VERSION 5.7 ;
  NOWIREEXTENSIONATPIN ON ;
  DIVIDERCHAR "/" ;
  BUSBITCHARS "[]" ;
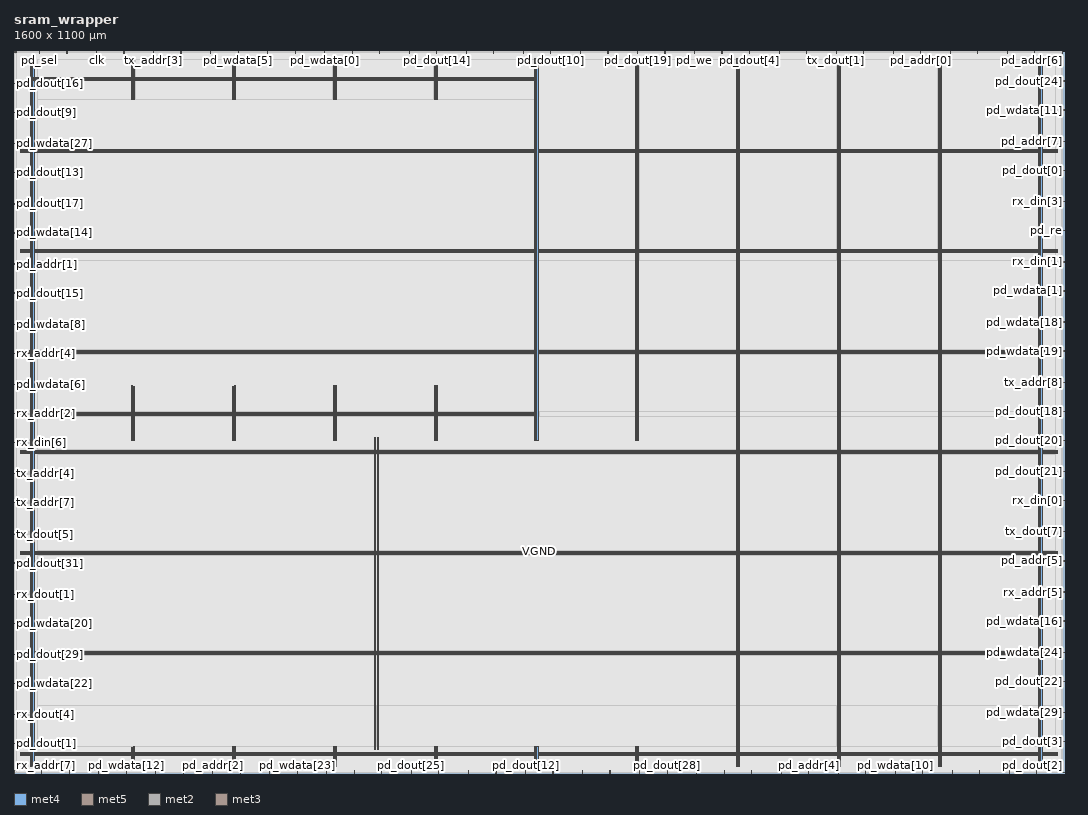
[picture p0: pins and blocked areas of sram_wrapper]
MACRO sram_wrapper
  CLASS BLOCK ;
  FOREIGN sram_wrapper ;
  ORIGIN 0.000 0.000 ;
  SIZE 1600.000 BY 1100.000 ;
  PIN VGND
    DIRECTION INOUT ;
    USE GROUND ;
    PORT
      LAYER met4 ;
        RECT 28.940 10.640 30.540 1088.240 ;
    END
    PORT
      LAYER met4 ;
        RECT 182.540 10.640 184.140 40.020 ;
    END
    PORT
      LAYER met4 ;
        RECT 182.540 506.440 184.140 589.400 ;
    END
    PORT
      LAYER met4 ;
        RECT 182.540 1026.520 184.140 1088.240 ;
    END
    PORT
      LAYER met4 ;
        RECT 336.140 10.640 337.740 40.020 ;
    END
    PORT
      LAYER met4 ;
        RECT 336.140 506.440 337.740 590.020 ;
    END
    PORT
      LAYER met4 ;
        RECT 336.140 1026.520 337.740 1088.240 ;
    END
    PORT
      LAYER met4 ;
        RECT 489.740 10.640 491.340 40.020 ;
    END
    PORT
      LAYER met4 ;
        RECT 489.740 506.440 491.340 590.020 ;
    END
    PORT
      LAYER met4 ;
        RECT 489.740 1026.520 491.340 1088.240 ;
    END
    PORT
      LAYER met4 ;
        RECT 643.340 10.640 644.940 40.020 ;
    END
    PORT
      LAYER met4 ;
        RECT 643.340 506.440 644.940 590.020 ;
    END
    PORT
      LAYER met4 ;
        RECT 643.340 1026.520 644.940 1088.240 ;
    END
    PORT
      LAYER met4 ;
        RECT 796.940 10.640 798.540 40.020 ;
    END
    PORT
      LAYER met4 ;
        RECT 796.940 506.440 798.540 1088.240 ;
    END
    PORT
      LAYER met4 ;
        RECT 950.540 10.640 952.140 40.020 ;
    END
    PORT
      LAYER met4 ;
        RECT 950.540 506.440 952.140 1088.240 ;
    END
    PORT
      LAYER met4 ;
        RECT 1104.140 10.640 1105.740 1088.240 ;
    END
    PORT
      LAYER met4 ;
        RECT 1257.740 10.640 1259.340 1088.240 ;
    END
    PORT
      LAYER met4 ;
        RECT 1411.340 10.640 1412.940 1088.240 ;
    END
    PORT
      LAYER met4 ;
        RECT 1564.940 10.640 1566.540 1088.240 ;
    END
    PORT
      LAYER met5 ;
        RECT 9.880 30.030 1590.000 31.630 ;
    END
    PORT
      LAYER met5 ;
        RECT 9.880 183.210 1590.000 184.810 ;
    END
    PORT
      LAYER met5 ;
        RECT 9.880 336.390 1590.000 337.990 ;
    END
    PORT
      LAYER met5 ;
        RECT 9.880 489.570 1590.000 491.170 ;
    END
    PORT
      LAYER met5 ;
        RECT 9.880 642.750 1590.000 644.350 ;
    END
    PORT
      LAYER met5 ;
        RECT 9.880 795.930 1590.000 797.530 ;
    END
    PORT
      LAYER met5 ;
        RECT 9.880 949.110 1590.000 950.710 ;
    END
    PORT
      LAYER met4 ;
        RECT 553.500 35.120 555.100 511.600 ;
    END
    PORT
      LAYER met5 ;
        RECT 25.640 548.300 798.540 549.900 ;
    END
    PORT
      LAYER met5 ;
        RECT 25.640 1058.300 798.540 1059.900 ;
    END
  END VGND
  PIN VPWR
    DIRECTION INOUT ;
    USE POWER ;
    PORT
      LAYER met4 ;
        RECT 25.640 10.640 27.240 1088.240 ;
    END
    PORT
      LAYER met4 ;
        RECT 179.240 10.640 180.840 39.400 ;
    END
    PORT
      LAYER met4 ;
        RECT 179.240 506.440 180.840 590.020 ;
    END
    PORT
      LAYER met4 ;
        RECT 179.240 1026.520 180.840 1088.240 ;
    END
    PORT
      LAYER met4 ;
        RECT 332.840 10.640 334.440 40.020 ;
    END
    PORT
      LAYER met4 ;
        RECT 332.840 506.440 334.440 589.400 ;
    END
    PORT
      LAYER met4 ;
        RECT 332.840 1026.520 334.440 1088.240 ;
    END
    PORT
      LAYER met4 ;
        RECT 486.440 10.640 488.040 40.020 ;
    END
    PORT
      LAYER met4 ;
        RECT 486.440 506.440 488.040 590.020 ;
    END
    PORT
      LAYER met4 ;
        RECT 486.440 1026.520 488.040 1088.240 ;
    END
    PORT
      LAYER met4 ;
        RECT 640.040 10.640 641.640 40.020 ;
    END
    PORT
      LAYER met4 ;
        RECT 640.040 506.440 641.640 590.020 ;
    END
    PORT
      LAYER met4 ;
        RECT 640.040 1026.520 641.640 1088.240 ;
    END
    PORT
      LAYER met4 ;
        RECT 793.640 10.640 795.240 40.020 ;
    END
    PORT
      LAYER met4 ;
        RECT 793.640 506.440 795.240 1088.240 ;
    END
    PORT
      LAYER met4 ;
        RECT 947.240 10.640 948.840 40.020 ;
    END
    PORT
      LAYER met4 ;
        RECT 947.240 506.440 948.840 1088.240 ;
    END
    PORT
      LAYER met4 ;
        RECT 1100.840 10.640 1102.440 1088.240 ;
    END
    PORT
      LAYER met4 ;
        RECT 1254.440 10.640 1256.040 1088.240 ;
    END
    PORT
      LAYER met4 ;
        RECT 1408.040 10.640 1409.640 1088.240 ;
    END
    PORT
      LAYER met4 ;
        RECT 1561.640 10.640 1563.240 1088.240 ;
    END
    PORT
      LAYER met5 ;
        RECT 9.880 26.730 1590.000 28.330 ;
    END
    PORT
      LAYER met5 ;
        RECT 9.880 179.910 1590.000 181.510 ;
    END
    PORT
      LAYER met5 ;
        RECT 9.880 333.090 1590.000 334.690 ;
    END
    PORT
      LAYER met5 ;
        RECT 9.880 486.270 1590.000 487.870 ;
    END
    PORT
      LAYER met5 ;
        RECT 9.880 639.450 1590.000 641.050 ;
    END
    PORT
      LAYER met5 ;
        RECT 9.880 792.630 1590.000 794.230 ;
    END
    PORT
      LAYER met5 ;
        RECT 9.880 945.810 1590.000 947.410 ;
    END
    PORT
      LAYER met4 ;
        RECT 549.820 35.120 551.420 511.600 ;
    END
    PORT
      LAYER met5 ;
        RECT 25.640 544.900 798.540 546.500 ;
    END
    PORT
      LAYER met5 ;
        RECT 25.640 1054.900 798.540 1056.500 ;
    END
  END VPWR
  PIN clk
    DIRECTION INPUT ;
    USE SIGNAL ;
    ANTENNAGATEAREA 1.286700 ;
    ANTENNADIFFAREA 0.434700 ;
    PORT
      LAYER met2 ;
        RECT 125.670 1096.000 125.950 1100.000 ;
    END
  END clk
  PIN pd_addr[0]
    DIRECTION INPUT ;
    USE SIGNAL ;
    ANTENNAGATEAREA 0.990000 ;
    PORT
      LAYER met2 ;
        RECT 1381.470 1096.000 1381.750 1100.000 ;
    END
  END pd_addr[0]
  PIN pd_addr[1]
    DIRECTION INPUT ;
    USE SIGNAL ;
    ANTENNAGATEAREA 0.495000 ;
    PORT
      LAYER met3 ;
        RECT 0.000 775.240 4.000 775.840 ;
    END
  END pd_addr[1]
  PIN pd_addr[2]
    DIRECTION INPUT ;
    USE SIGNAL ;
    ANTENNAGATEAREA 0.742500 ;
    PORT
      LAYER met2 ;
        RECT 302.770 0.000 303.050 4.000 ;
    END
  END pd_addr[2]
  PIN pd_addr[3]
    DIRECTION INPUT ;
    USE SIGNAL ;
    ANTENNAGATEAREA 0.990000 ;
    PORT
      LAYER met2 ;
        RECT 1468.410 1096.000 1468.690 1100.000 ;
    END
  END pd_addr[3]
  PIN pd_addr[4]
    DIRECTION INPUT ;
    USE SIGNAL ;
    ANTENNAGATEAREA 0.990000 ;
    PORT
      LAYER met2 ;
        RECT 1210.810 0.000 1211.090 4.000 ;
    END
  END pd_addr[4]
  PIN pd_addr[5]
    DIRECTION INPUT ;
    USE SIGNAL ;
    ANTENNAGATEAREA 0.990000 ;
    PORT
      LAYER met3 ;
        RECT 1596.000 323.040 1600.000 323.640 ;
    END
  END pd_addr[5]
  PIN pd_addr[6]
    DIRECTION INPUT ;
    USE SIGNAL ;
    ANTENNAGATEAREA 0.990000 ;
    PORT
      LAYER met2 ;
        RECT 1597.210 1096.000 1597.490 1100.000 ;
    END
  END pd_addr[6]
  PIN pd_addr[7]
    DIRECTION INPUT ;
    USE SIGNAL ;
    ANTENNAGATEAREA 0.990000 ;
    PORT
      LAYER met3 ;
        RECT 1596.000 962.240 1600.000 962.840 ;
    END
  END pd_addr[7]
  PIN pd_addr[8]
    DIRECTION INPUT ;
    USE SIGNAL ;
    ANTENNAGATEAREA 0.742500 ;
    PORT
      LAYER met2 ;
        RECT 904.910 1096.000 905.190 1100.000 ;
    END
  END pd_addr[8]
  PIN pd_dout[0]
    DIRECTION OUTPUT TRISTATE ;
    USE SIGNAL ;
    ANTENNADIFFAREA 0.445500 ;
    PORT
      LAYER met3 ;
        RECT 1596.000 918.040 1600.000 918.640 ;
    END
  END pd_dout[0]
  PIN pd_dout[10]
    DIRECTION OUTPUT TRISTATE ;
    USE SIGNAL ;
    ANTENNADIFFAREA 0.795200 ;
    PORT
      LAYER met2 ;
        RECT 817.970 1096.000 818.250 1100.000 ;
    END
  END pd_dout[10]
  PIN pd_dout[11]
    DIRECTION OUTPUT TRISTATE ;
    USE SIGNAL ;
    ANTENNADIFFAREA 0.795200 ;
    PORT
      LAYER met2 ;
        RECT 1555.350 1096.000 1555.630 1100.000 ;
    END
  END pd_dout[11]
  PIN pd_dout[12]
    DIRECTION OUTPUT TRISTATE ;
    USE SIGNAL ;
    ANTENNADIFFAREA 0.445500 ;
    PORT
      LAYER met2 ;
        RECT 779.330 0.000 779.610 4.000 ;
    END
  END pd_dout[12]
  PIN pd_dout[13]
    DIRECTION OUTPUT TRISTATE ;
    USE SIGNAL ;
    ANTENNADIFFAREA 0.445500 ;
    PORT
      LAYER met3 ;
        RECT 0.000 914.640 4.000 915.240 ;
    END
  END pd_dout[13]
  PIN pd_dout[14]
    DIRECTION OUTPUT TRISTATE ;
    USE SIGNAL ;
    ANTENNADIFFAREA 0.795200 ;
    PORT
      LAYER met2 ;
        RECT 644.090 1096.000 644.370 1100.000 ;
    END
  END pd_dout[14]
  PIN pd_dout[15]
    DIRECTION OUTPUT TRISTATE ;
    USE SIGNAL ;
    ANTENNADIFFAREA 0.445500 ;
    PORT
      LAYER met3 ;
        RECT 0.000 731.040 4.000 731.640 ;
    END
  END pd_dout[15]
  PIN pd_dout[16]
    DIRECTION OUTPUT TRISTATE ;
    USE SIGNAL ;
    ANTENNADIFFAREA 0.445500 ;
    PORT
      LAYER met3 ;
        RECT 0.000 1050.640 4.000 1051.240 ;
    END
  END pd_dout[16]
  PIN pd_dout[17]
    DIRECTION OUTPUT TRISTATE ;
    USE SIGNAL ;
    ANTENNADIFFAREA 0.445500 ;
    PORT
      LAYER met3 ;
        RECT 0.000 867.040 4.000 867.640 ;
    END
  END pd_dout[17]
  PIN pd_dout[18]
    DIRECTION OUTPUT TRISTATE ;
    USE SIGNAL ;
    ANTENNADIFFAREA 0.445500 ;
    PORT
      LAYER met3 ;
        RECT 1596.000 550.840 1600.000 551.440 ;
    END
  END pd_dout[18]
  PIN pd_dout[19]
    DIRECTION OUTPUT TRISTATE ;
    USE SIGNAL ;
    ANTENNADIFFAREA 0.795200 ;
    PORT
      LAYER met2 ;
        RECT 949.990 1096.000 950.270 1100.000 ;
    END
  END pd_dout[19]
  PIN pd_dout[1]
    DIRECTION OUTPUT TRISTATE ;
    USE SIGNAL ;
    ANTENNADIFFAREA 0.445500 ;
    PORT
      LAYER met3 ;
        RECT 0.000 44.240 4.000 44.840 ;
    END
  END pd_dout[1]
  PIN pd_dout[20]
    DIRECTION OUTPUT TRISTATE ;
    USE SIGNAL ;
    ANTENNADIFFAREA 0.445500 ;
    PORT
      LAYER met3 ;
        RECT 1596.000 506.640 1600.000 507.240 ;
    END
  END pd_dout[20]
  PIN pd_dout[21]
    DIRECTION OUTPUT TRISTATE ;
    USE SIGNAL ;
    ANTENNADIFFAREA 0.445500 ;
    PORT
      LAYER met3 ;
        RECT 1596.000 459.040 1600.000 459.640 ;
    END
  END pd_dout[21]
  PIN pd_dout[22]
    DIRECTION OUTPUT TRISTATE ;
    USE SIGNAL ;
    ANTENNADIFFAREA 0.445500 ;
    PORT
      LAYER met3 ;
        RECT 1596.000 139.440 1600.000 140.040 ;
    END
  END pd_dout[22]
  PIN pd_dout[23]
    DIRECTION OUTPUT TRISTATE ;
    USE SIGNAL ;
    ANTENNADIFFAREA 0.795200 ;
    PORT
      LAYER met2 ;
        RECT 991.850 1096.000 992.130 1100.000 ;
    END
  END pd_dout[23]
  PIN pd_dout[24]
    DIRECTION OUTPUT TRISTATE ;
    USE SIGNAL ;
    ANTENNADIFFAREA 0.445500 ;
    PORT
      LAYER met3 ;
        RECT 1596.000 1054.040 1600.000 1054.640 ;
    END
  END pd_dout[24]
  PIN pd_dout[25]
    DIRECTION OUTPUT TRISTATE ;
    USE SIGNAL ;
    ANTENNADIFFAREA 0.445500 ;
    PORT
      LAYER met2 ;
        RECT 605.450 0.000 605.730 4.000 ;
    END
  END pd_dout[25]
  PIN pd_dout[26]
    DIRECTION OUTPUT TRISTATE ;
    USE SIGNAL ;
    ANTENNADIFFAREA 0.445500 ;
    PORT
      LAYER met2 ;
        RECT 518.510 0.000 518.790 4.000 ;
    END
  END pd_dout[26]
  PIN pd_dout[27]
    DIRECTION OUTPUT TRISTATE ;
    USE SIGNAL ;
    ANTENNADIFFAREA 0.445500 ;
    PORT
      LAYER met2 ;
        RECT 389.710 0.000 389.990 4.000 ;
    END
  END pd_dout[27]
  PIN pd_dout[28]
    DIRECTION OUTPUT TRISTATE ;
    USE SIGNAL ;
    ANTENNADIFFAREA 0.445500 ;
    PORT
      LAYER met2 ;
        RECT 995.070 0.000 995.350 4.000 ;
    END
  END pd_dout[28]
  PIN pd_dout[29]
    DIRECTION OUTPUT TRISTATE ;
    USE SIGNAL ;
    ANTENNADIFFAREA 0.445500 ;
    PORT
      LAYER met3 ;
        RECT 0.000 180.240 4.000 180.840 ;
    END
  END pd_dout[29]
  PIN pd_dout[2]
    DIRECTION OUTPUT TRISTATE ;
    USE SIGNAL ;
    ANTENNADIFFAREA 0.445500 ;
    PORT
      LAYER met2 ;
        RECT 1558.570 0.000 1558.850 4.000 ;
    END
  END pd_dout[2]
  PIN pd_dout[30]
    DIRECTION OUTPUT TRISTATE ;
    USE SIGNAL ;
    ANTENNADIFFAREA 0.445500 ;
    PORT
      LAYER met2 ;
        RECT 344.630 0.000 344.910 4.000 ;
    END
  END pd_dout[30]
  PIN pd_dout[31]
    DIRECTION OUTPUT TRISTATE ;
    USE SIGNAL ;
    ANTENNADIFFAREA 0.445500 ;
    PORT
      LAYER met3 ;
        RECT 0.000 319.640 4.000 320.240 ;
    END
  END pd_dout[31]
  PIN pd_dout[3]
    DIRECTION OUTPUT TRISTATE ;
    USE SIGNAL ;
    ANTENNADIFFAREA 0.445500 ;
    PORT
      LAYER met3 ;
        RECT 1596.000 47.640 1600.000 48.240 ;
    END
  END pd_dout[3]
  PIN pd_dout[4]
    DIRECTION OUTPUT TRISTATE ;
    USE SIGNAL ;
    ANTENNADIFFAREA 0.795200 ;
    PORT
      LAYER met2 ;
        RECT 1120.650 1096.000 1120.930 1100.000 ;
    END
  END pd_dout[4]
  PIN pd_dout[5]
    DIRECTION OUTPUT TRISTATE ;
    USE SIGNAL ;
    ANTENNADIFFAREA 0.795200 ;
    PORT
      LAYER met2 ;
        RECT 602.230 1096.000 602.510 1100.000 ;
    END
  END pd_dout[5]
  PIN pd_dout[6]
    DIRECTION OUTPUT TRISTATE ;
    USE SIGNAL ;
    ANTENNADIFFAREA 0.795200 ;
    PORT
      LAYER met2 ;
        RECT 776.110 1096.000 776.390 1100.000 ;
    END
  END pd_dout[6]
  PIN pd_dout[7]
    DIRECTION OUTPUT TRISTATE ;
    USE SIGNAL ;
    ANTENNADIFFAREA 0.795200 ;
    PORT
      LAYER met2 ;
        RECT 1207.590 1096.000 1207.870 1100.000 ;
    END
  END pd_dout[7]
  PIN pd_dout[8]
    DIRECTION OUTPUT TRISTATE ;
    USE SIGNAL ;
    ANTENNADIFFAREA 0.445500 ;
    PORT
      LAYER met2 ;
        RECT 1082.010 0.000 1082.290 4.000 ;
    END
  END pd_dout[8]
  PIN pd_dout[9]
    DIRECTION OUTPUT TRISTATE ;
    USE SIGNAL ;
    ANTENNADIFFAREA 0.445500 ;
    PORT
      LAYER met3 ;
        RECT 0.000 1006.440 4.000 1007.040 ;
    END
  END pd_dout[9]
  PIN pd_re
    DIRECTION INPUT ;
    USE SIGNAL ;
    ANTENNAGATEAREA 0.742500 ;
    PORT
      LAYER met3 ;
        RECT 1596.000 826.240 1600.000 826.840 ;
    END
  END pd_re
  PIN pd_sel
    DIRECTION INPUT ;
    USE SIGNAL ;
    ANTENNAGATEAREA 0.742500 ;
    PORT
      LAYER met2 ;
        RECT 38.730 1096.000 39.010 1100.000 ;
    END
  END pd_sel
  PIN pd_wdata[0]
    DIRECTION INPUT ;
    USE SIGNAL ;
    ANTENNAGATEAREA 0.247500 ;
    PORT
      LAYER met2 ;
        RECT 473.430 1096.000 473.710 1100.000 ;
    END
  END pd_wdata[0]
  PIN pd_wdata[10]
    DIRECTION INPUT ;
    USE SIGNAL ;
    ANTENNAGATEAREA 0.852000 ;
    PORT
      LAYER met2 ;
        RECT 1342.830 0.000 1343.110 4.000 ;
    END
  END pd_wdata[10]
  PIN pd_wdata[11]
    DIRECTION INPUT ;
    USE SIGNAL ;
    ANTENNAGATEAREA 0.990000 ;
    PORT
      LAYER met3 ;
        RECT 1596.000 1009.840 1600.000 1010.440 ;
    END
  END pd_wdata[11]
  PIN pd_wdata[12]
    DIRECTION INPUT ;
    USE SIGNAL ;
    ANTENNAGATEAREA 0.247500 ;
    PORT
      LAYER met2 ;
        RECT 170.750 0.000 171.030 4.000 ;
    END
  END pd_wdata[12]
  PIN pd_wdata[13]
    DIRECTION INPUT ;
    USE SIGNAL ;
    ANTENNAGATEAREA 0.247500 ;
    PORT
      LAYER met3 ;
        RECT 0.000 1098.240 4.000 1098.840 ;
    END
  END pd_wdata[13]
  PIN pd_wdata[14]
    DIRECTION INPUT ;
    USE SIGNAL ;
    ANTENNAGATEAREA 0.213000 ;
    PORT
      LAYER met3 ;
        RECT 0.000 822.840 4.000 823.440 ;
    END
  END pd_wdata[14]
  PIN pd_wdata[15]
    DIRECTION INPUT ;
    USE SIGNAL ;
    ANTENNAGATEAREA 0.742500 ;
    PORT
      LAYER met2 ;
        RECT 821.190 0.000 821.470 4.000 ;
    END
  END pd_wdata[15]
  PIN pd_wdata[16]
    DIRECTION INPUT ;
    USE SIGNAL ;
    ANTENNAGATEAREA 0.852000 ;
    PORT
      LAYER met3 ;
        RECT 1596.000 231.240 1600.000 231.840 ;
    END
  END pd_wdata[16]
  PIN pd_wdata[17]
    DIRECTION INPUT ;
    USE SIGNAL ;
    ANTENNAGATEAREA 0.990000 ;
    PORT
      LAYER met2 ;
        RECT 1255.890 0.000 1256.170 4.000 ;
    END
  END pd_wdata[17]
  PIN pd_wdata[18]
    DIRECTION INPUT ;
    USE SIGNAL ;
    ANTENNAGATEAREA 0.742500 ;
    PORT
      LAYER met3 ;
        RECT 1596.000 686.840 1600.000 687.440 ;
    END
  END pd_wdata[18]
  PIN pd_wdata[19]
    DIRECTION INPUT ;
    USE SIGNAL ;
    ANTENNAGATEAREA 0.742500 ;
    PORT
      LAYER met3 ;
        RECT 1596.000 642.640 1600.000 643.240 ;
    END
  END pd_wdata[19]
  PIN pd_wdata[1]
    DIRECTION INPUT ;
    USE SIGNAL ;
    ANTENNAGATEAREA 0.990000 ;
    PORT
      LAYER met3 ;
        RECT 1596.000 734.440 1600.000 735.040 ;
    END
  END pd_wdata[1]
  PIN pd_wdata[20]
    DIRECTION INPUT ;
    USE SIGNAL ;
    ANTENNAGATEAREA 0.247500 ;
    PORT
      LAYER met3 ;
        RECT 0.000 227.840 4.000 228.440 ;
    END
  END pd_wdata[20]
  PIN pd_wdata[21]
    DIRECTION INPUT ;
    USE SIGNAL ;
    ANTENNAGATEAREA 0.495000 ;
    PORT
      LAYER met2 ;
        RECT 863.050 1096.000 863.330 1100.000 ;
    END
  END pd_wdata[21]
  PIN pd_wdata[22]
    DIRECTION INPUT ;
    USE SIGNAL ;
    ANTENNAGATEAREA 0.247500 ;
    PORT
      LAYER met3 ;
        RECT 0.000 136.040 4.000 136.640 ;
    END
  END pd_wdata[22]
  PIN pd_wdata[23]
    DIRECTION INPUT ;
    USE SIGNAL ;
    ANTENNAGATEAREA 0.247500 ;
    PORT
      LAYER met2 ;
        RECT 431.570 0.000 431.850 4.000 ;
    END
  END pd_wdata[23]
  PIN pd_wdata[24]
    DIRECTION INPUT ;
    USE SIGNAL ;
    ANTENNAGATEAREA 0.852000 ;
    PORT
      LAYER met3 ;
        RECT 1596.000 183.640 1600.000 184.240 ;
    END
  END pd_wdata[24]
  PIN pd_wdata[25]
    DIRECTION INPUT ;
    USE SIGNAL ;
    ANTENNAGATEAREA 0.247500 ;
    PORT
      LAYER met2 ;
        RECT 557.150 1096.000 557.430 1100.000 ;
    END
  END pd_wdata[25]
  PIN pd_wdata[26]
    DIRECTION INPUT ;
    USE SIGNAL ;
    ANTENNAGATEAREA 0.247500 ;
    PORT
      LAYER met2 ;
        RECT 428.350 1096.000 428.630 1100.000 ;
    END
  END pd_wdata[26]
  PIN pd_wdata[27]
    DIRECTION INPUT ;
    USE SIGNAL ;
    ANTENNAGATEAREA 0.247500 ;
    PORT
      LAYER met3 ;
        RECT 0.000 958.840 4.000 959.440 ;
    END
  END pd_wdata[27]
  PIN pd_wdata[28]
    DIRECTION INPUT ;
    USE SIGNAL ;
    ANTENNAGATEAREA 0.990000 ;
    PORT
      LAYER met2 ;
        RECT 1297.750 0.000 1298.030 4.000 ;
    END
  END pd_wdata[28]
  PIN pd_wdata[29]
    DIRECTION INPUT ;
    USE SIGNAL ;
    ANTENNAGATEAREA 0.990000 ;
    PORT
      LAYER met3 ;
        RECT 1596.000 91.840 1600.000 92.440 ;
    END
  END pd_wdata[29]
  PIN pd_wdata[2]
    DIRECTION INPUT ;
    USE SIGNAL ;
    ANTENNAGATEAREA 0.990000 ;
    PORT
      LAYER met2 ;
        RECT 1426.550 1096.000 1426.830 1100.000 ;
    END
  END pd_wdata[2]
  PIN pd_wdata[30]
    DIRECTION INPUT ;
    USE SIGNAL ;
    ANTENNAGATEAREA 0.990000 ;
    PORT
      LAYER met2 ;
        RECT 1471.630 0.000 1471.910 4.000 ;
    END
  END pd_wdata[30]
  PIN pd_wdata[31]
    DIRECTION INPUT ;
    USE SIGNAL ;
    ANTENNAGATEAREA 0.742500 ;
    PORT
      LAYER met2 ;
        RECT 1123.870 0.000 1124.150 4.000 ;
    END
  END pd_wdata[31]
  PIN pd_wdata[3]
    DIRECTION INPUT ;
    USE SIGNAL ;
    ANTENNAGATEAREA 0.426000 ;
    PORT
      LAYER met2 ;
        RECT 560.370 0.000 560.650 4.000 ;
    END
  END pd_wdata[3]
  PIN pd_wdata[4]
    DIRECTION INPUT ;
    USE SIGNAL ;
    ANTENNAGATEAREA 0.426000 ;
    PORT
      LAYER met2 ;
        RECT 689.170 1096.000 689.450 1100.000 ;
    END
  END pd_wdata[4]
  PIN pd_wdata[5]
    DIRECTION INPUT ;
    USE SIGNAL ;
    ANTENNAGATEAREA 0.247500 ;
    PORT
      LAYER met2 ;
        RECT 341.410 1096.000 341.690 1100.000 ;
    END
  END pd_wdata[5]
  PIN pd_wdata[6]
    DIRECTION INPUT ;
    USE SIGNAL ;
    ANTENNAGATEAREA 0.126000 ;
    PORT
      LAYER met3 ;
        RECT 0.000 591.640 4.000 592.240 ;
    END
  END pd_wdata[6]
  PIN pd_wdata[7]
    DIRECTION INPUT ;
    USE SIGNAL ;
    ANTENNAGATEAREA 0.990000 ;
    PORT
      LAYER met2 ;
        RECT 1429.770 0.000 1430.050 4.000 ;
    END
  END pd_wdata[7]
  PIN pd_wdata[8]
    DIRECTION INPUT ;
    USE SIGNAL ;
    ANTENNAGATEAREA 0.213000 ;
    PORT
      LAYER met3 ;
        RECT 0.000 683.440 4.000 684.040 ;
    END
  END pd_wdata[8]
  PIN pd_wdata[9]
    DIRECTION INPUT ;
    USE SIGNAL ;
    ANTENNAGATEAREA 0.247500 ;
    PORT
      LAYER met2 ;
        RECT 386.490 1096.000 386.770 1100.000 ;
    END
  END pd_wdata[9]
  PIN pd_we
    DIRECTION INPUT ;
    USE SIGNAL ;
    ANTENNAGATEAREA 0.495000 ;
    PORT
      LAYER met2 ;
        RECT 1036.930 1096.000 1037.210 1100.000 ;
    END
  END pd_we
  PIN rx_addr[0]
    DIRECTION INPUT ;
    USE SIGNAL ;
    ANTENNAGATEAREA 0.742500 ;
    PORT
      LAYER met2 ;
        RECT 953.210 0.000 953.490 4.000 ;
    END
  END rx_addr[0]
  PIN rx_addr[1]
    DIRECTION INPUT ;
    USE SIGNAL ;
    ANTENNAGATEAREA 0.247500 ;
    PORT
      LAYER met2 ;
        RECT 128.890 0.000 129.170 4.000 ;
    END
  END rx_addr[1]
  PIN rx_addr[2]
    DIRECTION INPUT ;
    USE SIGNAL ;
    ANTENNAGATEAREA 0.426000 ;
    PORT
      LAYER met3 ;
        RECT 0.000 547.440 4.000 548.040 ;
    END
  END rx_addr[2]
  PIN rx_addr[3]
    DIRECTION INPUT ;
    USE SIGNAL ;
    ANTENNAGATEAREA 0.852000 ;
    PORT
      LAYER met2 ;
        RECT 1384.690 0.000 1384.970 4.000 ;
    END
  END rx_addr[3]
  PIN rx_addr[4]
    DIRECTION INPUT ;
    USE SIGNAL ;
    ANTENNAGATEAREA 0.495000 ;
    PORT
      LAYER met3 ;
        RECT 0.000 639.240 4.000 639.840 ;
    END
  END rx_addr[4]
  PIN rx_addr[5]
    DIRECTION INPUT ;
    USE SIGNAL ;
    ANTENNAGATEAREA 0.852000 ;
    PORT
      LAYER met3 ;
        RECT 1596.000 275.440 1600.000 276.040 ;
    END
  END rx_addr[5]
  PIN rx_addr[6]
    DIRECTION INPUT ;
    USE SIGNAL ;
    ANTENNAGATEAREA 0.742500 ;
    PORT
      LAYER met2 ;
        RECT 1040.150 0.000 1040.430 4.000 ;
    END
  END rx_addr[6]
  PIN rx_addr[7]
    DIRECTION INPUT ;
    USE SIGNAL ;
    ANTENNAGATEAREA 0.247500 ;
    PORT
      LAYER met2 ;
        RECT 41.950 0.000 42.230 4.000 ;
    END
  END rx_addr[7]
  PIN rx_addr[8]
    DIRECTION INPUT ;
    USE SIGNAL ;
    ANTENNAGATEAREA 0.990000 ;
    PORT
      LAYER met3 ;
        RECT 1596.000 0.040 1600.000 0.640 ;
    END
  END rx_addr[8]
  PIN rx_addr[9]
    DIRECTION INPUT ;
    USE SIGNAL ;
    ANTENNAGATEAREA 0.742500 ;
    PORT
      LAYER met2 ;
        RECT 167.530 1096.000 167.810 1100.000 ;
    END
  END rx_addr[9]
  PIN rx_din[0]
    DIRECTION INPUT ;
    USE SIGNAL ;
    ANTENNAGATEAREA 0.990000 ;
    PORT
      LAYER met3 ;
        RECT 1596.000 414.840 1600.000 415.440 ;
    END
  END rx_din[0]
  PIN rx_din[1]
    DIRECTION INPUT ;
    USE SIGNAL ;
    ANTENNAGATEAREA 0.990000 ;
    PORT
      LAYER met3 ;
        RECT 1596.000 778.640 1600.000 779.240 ;
    END
  END rx_din[1]
  PIN rx_din[2]
    DIRECTION INPUT ;
    USE SIGNAL ;
    ANTENNAGATEAREA 0.495000 ;
    PORT
      LAYER met2 ;
        RECT 1168.950 0.000 1169.230 4.000 ;
    END
  END rx_din[2]
  PIN rx_din[3]
    DIRECTION INPUT ;
    USE SIGNAL ;
    ANTENNAGATEAREA 0.990000 ;
    PORT
      LAYER met3 ;
        RECT 1596.000 870.440 1600.000 871.040 ;
    END
  END rx_din[3]
  PIN rx_din[4]
    DIRECTION INPUT ;
    USE SIGNAL ;
    ANTENNAGATEAREA 0.213000 ;
    PORT
      LAYER met2 ;
        RECT 692.390 0.000 692.670 4.000 ;
    END
  END rx_din[4]
  PIN rx_din[5]
    DIRECTION INPUT ;
    USE SIGNAL ;
    ANTENNAGATEAREA 0.495000 ;
    PORT
      LAYER met2 ;
        RECT 254.470 1096.000 254.750 1100.000 ;
    END
  END rx_din[5]
  PIN rx_din[6]
    DIRECTION INPUT ;
    USE SIGNAL ;
    ANTENNAGATEAREA 0.247500 ;
    PORT
      LAYER met3 ;
        RECT 0.000 503.240 4.000 503.840 ;
    END
  END rx_din[6]
  PIN rx_din[7]
    DIRECTION INPUT ;
    USE SIGNAL ;
    ANTENNAGATEAREA 0.126000 ;
    PORT
      LAYER met2 ;
        RECT 0.090 0.000 0.370 4.000 ;
    END
  END rx_din[7]
  PIN rx_dout[0]
    DIRECTION OUTPUT TRISTATE ;
    USE SIGNAL ;
    ANTENNADIFFAREA 0.445500 ;
    PORT
      LAYER met2 ;
        RECT 866.270 0.000 866.550 4.000 ;
    END
  END rx_dout[0]
  PIN rx_dout[1]
    DIRECTION OUTPUT TRISTATE ;
    USE SIGNAL ;
    ANTENNADIFFAREA 0.445500 ;
    PORT
      LAYER met3 ;
        RECT 0.000 272.040 4.000 272.640 ;
    END
  END rx_dout[1]
  PIN rx_dout[2]
    DIRECTION OUTPUT TRISTATE ;
    USE SIGNAL ;
    ANTENNADIFFAREA 0.795200 ;
    PORT
      LAYER met2 ;
        RECT 731.030 1096.000 731.310 1100.000 ;
    END
  END rx_dout[2]
  PIN rx_dout[3]
    DIRECTION OUTPUT TRISTATE ;
    USE SIGNAL ;
    ANTENNADIFFAREA 0.795200 ;
    PORT
      LAYER met2 ;
        RECT 1165.730 1096.000 1166.010 1100.000 ;
    END
  END rx_dout[3]
  PIN rx_dout[4]
    DIRECTION OUTPUT TRISTATE ;
    USE SIGNAL ;
    ANTENNADIFFAREA 0.445500 ;
    PORT
      LAYER met3 ;
        RECT 0.000 88.440 4.000 89.040 ;
    END
  END rx_dout[4]
  PIN rx_dout[5]
    DIRECTION OUTPUT TRISTATE ;
    USE SIGNAL ;
    ANTENNADIFFAREA 0.445500 ;
    PORT
      LAYER met2 ;
        RECT 215.830 0.000 216.110 4.000 ;
    END
  END rx_dout[5]
  PIN rx_dout[6]
    DIRECTION OUTPUT TRISTATE ;
    USE SIGNAL ;
    ANTENNADIFFAREA 0.445500 ;
    PORT
      LAYER met2 ;
        RECT 83.810 0.000 84.090 4.000 ;
    END
  END rx_dout[6]
  PIN rx_dout[7]
    DIRECTION OUTPUT TRISTATE ;
    USE SIGNAL ;
    ANTENNADIFFAREA 0.795200 ;
    PORT
      LAYER met2 ;
        RECT 1339.610 1096.000 1339.890 1100.000 ;
    END
  END rx_dout[7]
  PIN rx_we
    DIRECTION INPUT ;
    USE SIGNAL ;
    ANTENNAGATEAREA 0.742500 ;
    PORT
      LAYER met2 ;
        RECT 1078.790 1096.000 1079.070 1100.000 ;
    END
  END rx_we
  PIN tx_addr[0]
    DIRECTION INPUT ;
    USE SIGNAL ;
    ANTENNAGATEAREA 0.426000 ;
    PORT
      LAYER met2 ;
        RECT 647.310 0.000 647.590 4.000 ;
    END
  END tx_addr[0]
  PIN tx_addr[1]
    DIRECTION INPUT ;
    USE SIGNAL ;
    ANTENNAGATEAREA 0.990000 ;
    PORT
      LAYER met2 ;
        RECT 1513.490 1096.000 1513.770 1100.000 ;
    END
  END tx_addr[1]
  PIN tx_addr[2]
    DIRECTION INPUT ;
    USE SIGNAL ;
    ANTENNAGATEAREA 0.742500 ;
    PORT
      LAYER met2 ;
        RECT 1516.710 0.000 1516.990 4.000 ;
    END
  END tx_addr[2]
  PIN tx_addr[3]
    DIRECTION INPUT ;
    USE SIGNAL ;
    ANTENNAGATEAREA 0.990000 ;
    PORT
      LAYER met2 ;
        RECT 212.610 1096.000 212.890 1100.000 ;
    END
  END tx_addr[3]
  PIN tx_addr[4]
    DIRECTION INPUT ;
    USE SIGNAL ;
    ANTENNAGATEAREA 0.742500 ;
    PORT
      LAYER met3 ;
        RECT 0.000 455.640 4.000 456.240 ;
    END
  END tx_addr[4]
  PIN tx_addr[5]
    DIRECTION INPUT ;
    USE SIGNAL ;
    ANTENNAGATEAREA 0.495000 ;
    PORT
      LAYER met2 ;
        RECT 257.690 0.000 257.970 4.000 ;
    END
  END tx_addr[5]
  PIN tx_addr[6]
    DIRECTION INPUT ;
    USE SIGNAL ;
    ANTENNAGATEAREA 0.247500 ;
    PORT
      LAYER met2 ;
        RECT 476.650 0.000 476.930 4.000 ;
    END
  END tx_addr[6]
  PIN tx_addr[7]
    DIRECTION INPUT ;
    USE SIGNAL ;
    ANTENNAGATEAREA 0.742500 ;
    PORT
      LAYER met3 ;
        RECT 0.000 411.440 4.000 412.040 ;
    END
  END tx_addr[7]
  PIN tx_addr[8]
    DIRECTION INPUT ;
    USE SIGNAL ;
    ANTENNAGATEAREA 0.852000 ;
    PORT
      LAYER met3 ;
        RECT 1596.000 595.040 1600.000 595.640 ;
    END
  END tx_addr[8]
  PIN tx_addr[9]
    DIRECTION INPUT ;
    USE SIGNAL ;
    ANTENNAGATEAREA 0.247500 ;
    PORT
      LAYER met2 ;
        RECT 734.250 0.000 734.530 4.000 ;
    END
  END tx_addr[9]
  PIN tx_dout[0]
    DIRECTION OUTPUT TRISTATE ;
    USE SIGNAL ;
    ANTENNADIFFAREA 0.795200 ;
    PORT
      LAYER met2 ;
        RECT 1294.530 1096.000 1294.810 1100.000 ;
    END
  END tx_dout[0]
  PIN tx_dout[1]
    DIRECTION OUTPUT TRISTATE ;
    USE SIGNAL ;
    ANTENNADIFFAREA 0.795200 ;
    PORT
      LAYER met2 ;
        RECT 1252.670 1096.000 1252.950 1100.000 ;
    END
  END tx_dout[1]
  PIN tx_dout[2]
    DIRECTION OUTPUT TRISTATE ;
    USE SIGNAL ;
    ANTENNADIFFAREA 0.795200 ;
    PORT
      LAYER met2 ;
        RECT 299.550 1096.000 299.830 1100.000 ;
    END
  END tx_dout[2]
  PIN tx_dout[3]
    DIRECTION OUTPUT TRISTATE ;
    USE SIGNAL ;
    ANTENNADIFFAREA 0.795200 ;
    PORT
      LAYER met2 ;
        RECT 515.290 1096.000 515.570 1100.000 ;
    END
  END tx_dout[3]
  PIN tx_dout[4]
    DIRECTION OUTPUT TRISTATE ;
    USE SIGNAL ;
    ANTENNADIFFAREA 0.445500 ;
    PORT
      LAYER met2 ;
        RECT 908.130 0.000 908.410 4.000 ;
    END
  END tx_dout[4]
  PIN tx_dout[5]
    DIRECTION OUTPUT TRISTATE ;
    USE SIGNAL ;
    ANTENNADIFFAREA 0.445500 ;
    PORT
      LAYER met3 ;
        RECT 0.000 363.840 4.000 364.440 ;
    END
  END tx_dout[5]
  PIN tx_dout[6]
    DIRECTION OUTPUT TRISTATE ;
    USE SIGNAL ;
    ANTENNADIFFAREA 0.795200 ;
    PORT
      LAYER met2 ;
        RECT 80.590 1096.000 80.870 1100.000 ;
    END
  END tx_dout[6]
  PIN tx_dout[7]
    DIRECTION OUTPUT TRISTATE ;
    USE SIGNAL ;
    ANTENNADIFFAREA 0.445500 ;
    PORT
      LAYER met3 ;
        RECT 1596.000 367.240 1600.000 367.840 ;
    END
  END tx_dout[7]
  OBS
      LAYER li1 ;
        RECT 10.120 10.795 1589.760 1088.085 ;
      LAYER met1 ;
        RECT 0.070 7.520 1597.510 1088.240 ;
      LAYER met2 ;
        RECT 0.100 1095.720 38.450 1098.725 ;
        RECT 39.290 1095.720 80.310 1098.725 ;
        RECT 81.150 1095.720 125.390 1098.725 ;
        RECT 126.230 1095.720 167.250 1098.725 ;
        RECT 168.090 1095.720 212.330 1098.725 ;
        RECT 213.170 1095.720 254.190 1098.725 ;
        RECT 255.030 1095.720 299.270 1098.725 ;
        RECT 300.110 1095.720 341.130 1098.725 ;
        RECT 341.970 1095.720 386.210 1098.725 ;
        RECT 387.050 1095.720 428.070 1098.725 ;
        RECT 428.910 1095.720 473.150 1098.725 ;
        RECT 473.990 1095.720 515.010 1098.725 ;
        RECT 515.850 1095.720 556.870 1098.725 ;
        RECT 557.710 1095.720 601.950 1098.725 ;
        RECT 602.790 1095.720 643.810 1098.725 ;
        RECT 644.650 1095.720 688.890 1098.725 ;
        RECT 689.730 1095.720 730.750 1098.725 ;
        RECT 731.590 1095.720 775.830 1098.725 ;
        RECT 776.670 1095.720 817.690 1098.725 ;
        RECT 818.530 1095.720 862.770 1098.725 ;
        RECT 863.610 1095.720 904.630 1098.725 ;
        RECT 905.470 1095.720 949.710 1098.725 ;
        RECT 950.550 1095.720 991.570 1098.725 ;
        RECT 992.410 1095.720 1036.650 1098.725 ;
        RECT 1037.490 1095.720 1078.510 1098.725 ;
        RECT 1079.350 1095.720 1120.370 1098.725 ;
        RECT 1121.210 1095.720 1165.450 1098.725 ;
        RECT 1166.290 1095.720 1207.310 1098.725 ;
        RECT 1208.150 1095.720 1252.390 1098.725 ;
        RECT 1253.230 1095.720 1294.250 1098.725 ;
        RECT 1295.090 1095.720 1339.330 1098.725 ;
        RECT 1340.170 1095.720 1381.190 1098.725 ;
        RECT 1382.030 1095.720 1426.270 1098.725 ;
        RECT 1427.110 1095.720 1468.130 1098.725 ;
        RECT 1468.970 1095.720 1513.210 1098.725 ;
        RECT 1514.050 1095.720 1555.070 1098.725 ;
        RECT 1555.910 1095.720 1596.930 1098.725 ;
        RECT 0.100 4.280 1597.480 1095.720 ;
        RECT 0.650 0.155 41.670 4.280 ;
        RECT 42.510 0.155 83.530 4.280 ;
        RECT 84.370 0.155 128.610 4.280 ;
        RECT 129.450 0.155 170.470 4.280 ;
        RECT 171.310 0.155 215.550 4.280 ;
        RECT 216.390 0.155 257.410 4.280 ;
        RECT 258.250 0.155 302.490 4.280 ;
        RECT 303.330 0.155 344.350 4.280 ;
        RECT 345.190 0.155 389.430 4.280 ;
        RECT 390.270 0.155 431.290 4.280 ;
        RECT 432.130 0.155 476.370 4.280 ;
        RECT 477.210 0.155 518.230 4.280 ;
        RECT 519.070 0.155 560.090 4.280 ;
        RECT 560.930 0.155 605.170 4.280 ;
        RECT 606.010 0.155 647.030 4.280 ;
        RECT 647.870 0.155 692.110 4.280 ;
        RECT 692.950 0.155 733.970 4.280 ;
        RECT 734.810 0.155 779.050 4.280 ;
        RECT 779.890 0.155 820.910 4.280 ;
        RECT 821.750 0.155 865.990 4.280 ;
        RECT 866.830 0.155 907.850 4.280 ;
        RECT 908.690 0.155 952.930 4.280 ;
        RECT 953.770 0.155 994.790 4.280 ;
        RECT 995.630 0.155 1039.870 4.280 ;
        RECT 1040.710 0.155 1081.730 4.280 ;
        RECT 1082.570 0.155 1123.590 4.280 ;
        RECT 1124.430 0.155 1168.670 4.280 ;
        RECT 1169.510 0.155 1210.530 4.280 ;
        RECT 1211.370 0.155 1255.610 4.280 ;
        RECT 1256.450 0.155 1297.470 4.280 ;
        RECT 1298.310 0.155 1342.550 4.280 ;
        RECT 1343.390 0.155 1384.410 4.280 ;
        RECT 1385.250 0.155 1429.490 4.280 ;
        RECT 1430.330 0.155 1471.350 4.280 ;
        RECT 1472.190 0.155 1516.430 4.280 ;
        RECT 1517.270 0.155 1558.290 4.280 ;
        RECT 1559.130 0.155 1597.480 4.280 ;
      LAYER met3 ;
        RECT 4.400 1097.840 1596.000 1098.705 ;
        RECT 4.000 1055.040 1596.000 1097.840 ;
        RECT 4.000 1053.640 1595.600 1055.040 ;
        RECT 4.000 1051.640 1596.000 1053.640 ;
        RECT 4.400 1050.240 1596.000 1051.640 ;
        RECT 4.000 1010.840 1596.000 1050.240 ;
        RECT 4.000 1009.440 1595.600 1010.840 ;
        RECT 4.000 1007.440 1596.000 1009.440 ;
        RECT 4.400 1006.040 1596.000 1007.440 ;
        RECT 4.000 963.240 1596.000 1006.040 ;
        RECT 4.000 961.840 1595.600 963.240 ;
        RECT 4.000 959.840 1596.000 961.840 ;
        RECT 4.400 958.440 1596.000 959.840 ;
        RECT 4.000 919.040 1596.000 958.440 ;
        RECT 4.000 917.640 1595.600 919.040 ;
        RECT 4.000 915.640 1596.000 917.640 ;
        RECT 4.400 914.240 1596.000 915.640 ;
        RECT 4.000 871.440 1596.000 914.240 ;
        RECT 4.000 870.040 1595.600 871.440 ;
        RECT 4.000 868.040 1596.000 870.040 ;
        RECT 4.400 866.640 1596.000 868.040 ;
        RECT 4.000 827.240 1596.000 866.640 ;
        RECT 4.000 825.840 1595.600 827.240 ;
        RECT 4.000 823.840 1596.000 825.840 ;
        RECT 4.400 822.440 1596.000 823.840 ;
        RECT 4.000 779.640 1596.000 822.440 ;
        RECT 4.000 778.240 1595.600 779.640 ;
        RECT 4.000 776.240 1596.000 778.240 ;
        RECT 4.400 774.840 1596.000 776.240 ;
        RECT 4.000 735.440 1596.000 774.840 ;
        RECT 4.000 734.040 1595.600 735.440 ;
        RECT 4.000 732.040 1596.000 734.040 ;
        RECT 4.400 730.640 1596.000 732.040 ;
        RECT 4.000 687.840 1596.000 730.640 ;
        RECT 4.000 686.440 1595.600 687.840 ;
        RECT 4.000 684.440 1596.000 686.440 ;
        RECT 4.400 683.040 1596.000 684.440 ;
        RECT 4.000 643.640 1596.000 683.040 ;
        RECT 4.000 642.240 1595.600 643.640 ;
        RECT 4.000 640.240 1596.000 642.240 ;
        RECT 4.400 638.840 1596.000 640.240 ;
        RECT 4.000 596.040 1596.000 638.840 ;
        RECT 4.000 594.640 1595.600 596.040 ;
        RECT 4.000 592.640 1596.000 594.640 ;
        RECT 4.400 591.240 1596.000 592.640 ;
        RECT 4.000 551.840 1596.000 591.240 ;
        RECT 4.000 550.440 1595.600 551.840 ;
        RECT 4.000 548.440 1596.000 550.440 ;
        RECT 4.400 547.040 1596.000 548.440 ;
        RECT 4.000 507.640 1596.000 547.040 ;
        RECT 4.000 506.240 1595.600 507.640 ;
        RECT 4.000 504.240 1596.000 506.240 ;
        RECT 4.400 502.840 1596.000 504.240 ;
        RECT 4.000 460.040 1596.000 502.840 ;
        RECT 4.000 458.640 1595.600 460.040 ;
        RECT 4.000 456.640 1596.000 458.640 ;
        RECT 4.400 455.240 1596.000 456.640 ;
        RECT 4.000 415.840 1596.000 455.240 ;
        RECT 4.000 414.440 1595.600 415.840 ;
        RECT 4.000 412.440 1596.000 414.440 ;
        RECT 4.400 411.040 1596.000 412.440 ;
        RECT 4.000 368.240 1596.000 411.040 ;
        RECT 4.000 366.840 1595.600 368.240 ;
        RECT 4.000 364.840 1596.000 366.840 ;
        RECT 4.400 363.440 1596.000 364.840 ;
        RECT 4.000 324.040 1596.000 363.440 ;
        RECT 4.000 322.640 1595.600 324.040 ;
        RECT 4.000 320.640 1596.000 322.640 ;
        RECT 4.400 319.240 1596.000 320.640 ;
        RECT 4.000 276.440 1596.000 319.240 ;
        RECT 4.000 275.040 1595.600 276.440 ;
        RECT 4.000 273.040 1596.000 275.040 ;
        RECT 4.400 271.640 1596.000 273.040 ;
        RECT 4.000 232.240 1596.000 271.640 ;
        RECT 4.000 230.840 1595.600 232.240 ;
        RECT 4.000 228.840 1596.000 230.840 ;
        RECT 4.400 227.440 1596.000 228.840 ;
        RECT 4.000 184.640 1596.000 227.440 ;
        RECT 4.000 183.240 1595.600 184.640 ;
        RECT 4.000 181.240 1596.000 183.240 ;
        RECT 4.400 179.840 1596.000 181.240 ;
        RECT 4.000 140.440 1596.000 179.840 ;
        RECT 4.000 139.040 1595.600 140.440 ;
        RECT 4.000 137.040 1596.000 139.040 ;
        RECT 4.400 135.640 1596.000 137.040 ;
        RECT 4.000 92.840 1596.000 135.640 ;
        RECT 4.000 91.440 1595.600 92.840 ;
        RECT 4.000 89.440 1596.000 91.440 ;
        RECT 4.400 88.040 1596.000 89.440 ;
        RECT 4.000 48.640 1596.000 88.040 ;
        RECT 4.000 47.240 1595.600 48.640 ;
        RECT 4.000 45.240 1596.000 47.240 ;
        RECT 4.400 43.840 1596.000 45.240 ;
        RECT 4.000 1.040 1596.000 43.840 ;
        RECT 4.000 0.175 1595.600 1.040 ;
      LAYER met4 ;
        RECT 35.750 1026.120 178.840 1087.145 ;
        RECT 181.240 1026.120 182.140 1087.145 ;
        RECT 184.540 1026.120 332.440 1087.145 ;
        RECT 334.840 1026.120 335.740 1087.145 ;
        RECT 338.140 1026.120 486.040 1087.145 ;
        RECT 488.440 1026.120 489.340 1087.145 ;
        RECT 491.740 1026.120 639.640 1087.145 ;
        RECT 642.040 1026.120 642.940 1087.145 ;
        RECT 645.340 1026.120 793.240 1087.145 ;
        RECT 35.750 590.420 793.240 1026.120 ;
        RECT 35.750 506.040 178.840 590.420 ;
        RECT 181.240 589.800 335.740 590.420 ;
        RECT 181.240 506.040 182.140 589.800 ;
        RECT 184.540 506.040 332.440 589.800 ;
        RECT 334.840 506.040 335.740 589.800 ;
        RECT 338.140 506.040 486.040 590.420 ;
        RECT 488.440 506.040 489.340 590.420 ;
        RECT 491.740 512.000 639.640 590.420 ;
        RECT 491.740 506.040 549.420 512.000 ;
        RECT 35.750 40.420 549.420 506.040 ;
        RECT 35.750 40.295 182.140 40.420 ;
        RECT 184.540 40.295 332.440 40.420 ;
        RECT 334.840 40.295 335.740 40.420 ;
        RECT 338.140 40.295 486.040 40.420 ;
        RECT 488.440 40.295 489.340 40.420 ;
        RECT 491.740 40.295 549.420 40.420 ;
        RECT 551.820 40.295 553.100 512.000 ;
        RECT 555.500 506.040 639.640 512.000 ;
        RECT 642.040 506.040 642.940 590.420 ;
        RECT 645.340 506.040 793.240 590.420 ;
        RECT 795.640 506.040 796.540 1087.145 ;
        RECT 798.940 506.040 946.840 1087.145 ;
        RECT 949.240 506.040 950.140 1087.145 ;
        RECT 952.540 506.040 1100.440 1087.145 ;
        RECT 555.500 40.420 1100.440 506.040 ;
        RECT 555.500 40.295 639.640 40.420 ;
        RECT 642.040 40.295 642.940 40.420 ;
        RECT 645.340 40.295 793.240 40.420 ;
        RECT 795.640 40.295 796.540 40.420 ;
        RECT 798.940 40.295 946.840 40.420 ;
        RECT 949.240 40.295 950.140 40.420 ;
        RECT 952.540 40.295 1100.440 40.420 ;
        RECT 1102.840 40.295 1103.740 1087.145 ;
        RECT 1106.140 40.295 1254.040 1087.145 ;
        RECT 1256.440 40.295 1257.340 1087.145 ;
        RECT 1259.740 40.295 1407.640 1087.145 ;
        RECT 1410.040 40.295 1410.940 1087.145 ;
        RECT 1413.340 40.295 1561.240 1087.145 ;
        RECT 1563.640 40.295 1564.540 1087.145 ;
        RECT 1566.940 40.295 1587.130 1087.145 ;
      LAYER met5 ;
        RECT 35.540 645.950 1587.340 781.100 ;
        RECT 35.540 551.500 1587.340 637.850 ;
        RECT 800.140 543.300 1587.340 551.500 ;
        RECT 35.540 492.770 1587.340 543.300 ;
        RECT 35.540 339.590 1587.340 484.670 ;
        RECT 35.540 186.410 1587.340 331.490 ;
        RECT 35.540 102.900 1587.340 178.310 ;
  END
END sram_wrapper
END LIBRARY

